VERSION 5.7 ;
  NOWIREEXTENSIONATPIN ON ;
  DIVIDERCHAR "/" ;
  BUSBITCHARS "[]" ;
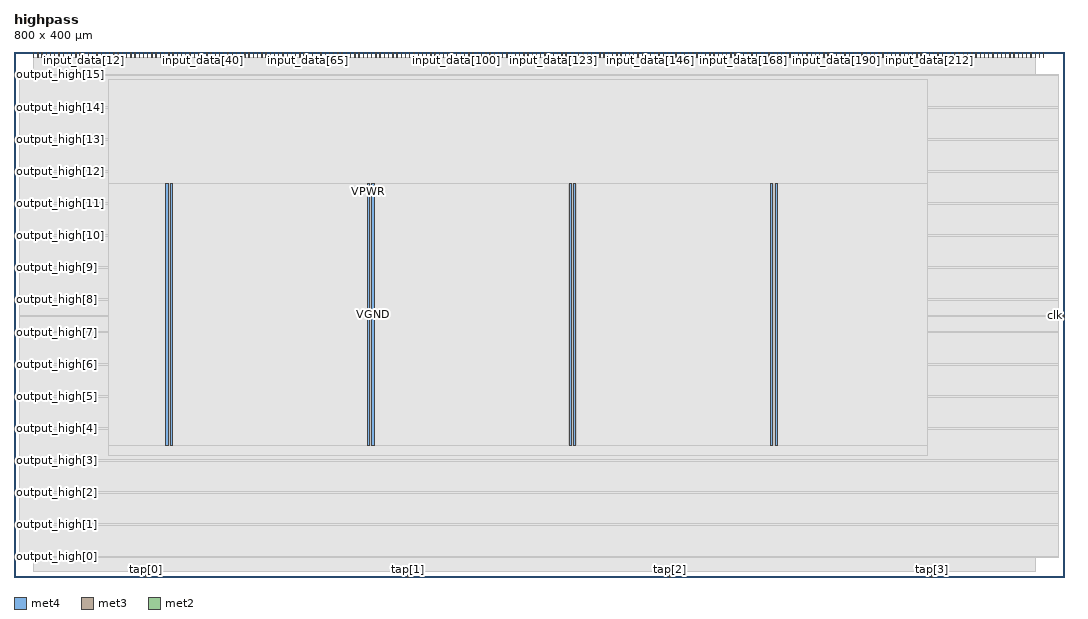
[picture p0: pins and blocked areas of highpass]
MACRO highpass
  CLASS BLOCK ;
  FOREIGN highpass ;
  ORIGIN 0.000 0.000 ;
  SIZE 800.000 BY 400.000 ;
  PIN VGND
    DIRECTION INOUT ;
    USE GROUND ;
    PORT
      LAYER met4 ;
        RECT 119.100 100.400 120.700 299.440 ;
    END
    PORT
      LAYER met4 ;
        RECT 272.700 100.400 274.300 299.440 ;
    END
    PORT
      LAYER met4 ;
        RECT 426.300 100.400 427.900 299.440 ;
    END
    PORT
      LAYER met4 ;
        RECT 579.900 100.400 581.500 299.440 ;
    END
  END VGND
  PIN VPWR
    DIRECTION INOUT ;
    USE POWER ;
    PORT
      LAYER met4 ;
        RECT 115.800 100.400 117.400 299.440 ;
    END
    PORT
      LAYER met4 ;
        RECT 269.400 100.400 271.000 299.440 ;
    END
    PORT
      LAYER met4 ;
        RECT 423.000 100.400 424.600 299.440 ;
    END
    PORT
      LAYER met4 ;
        RECT 576.600 100.400 578.200 299.440 ;
    END
  END VPWR
  PIN clk
    DIRECTION INPUT ;
    USE SIGNAL ;
    ANTENNAGATEAREA 0.852000 ;
    ANTENNADIFFAREA 0.434700 ;
    PORT
      LAYER met3 ;
        RECT 796.000 198.600 800.000 199.200 ;
    END
  END clk
  PIN input_data[0]
    DIRECTION INPUT ;
    USE SIGNAL ;
    ANTENNAGATEAREA 0.213000 ;
    ANTENNADIFFAREA 0.869400 ;
    PORT
      LAYER met2 ;
        RECT 14.810 396.000 15.090 400.000 ;
    END
  END input_data[0]
  PIN input_data[100]
    DIRECTION INPUT ;
    USE SIGNAL ;
    ANTENNAGATEAREA 0.196500 ;
    ANTENNADIFFAREA 0.434700 ;
    PORT
      LAYER met2 ;
        RECT 336.810 396.000 337.090 400.000 ;
    END
  END input_data[100]
  PIN input_data[101]
    DIRECTION INPUT ;
    USE SIGNAL ;
    ANTENNAGATEAREA 0.196500 ;
    ANTENNADIFFAREA 0.434700 ;
    PORT
      LAYER met2 ;
        RECT 340.030 396.000 340.310 400.000 ;
    END
  END input_data[101]
  PIN input_data[102]
    DIRECTION INPUT ;
    USE SIGNAL ;
    ANTENNAGATEAREA 0.213000 ;
    ANTENNADIFFAREA 0.434700 ;
    PORT
      LAYER met2 ;
        RECT 343.250 396.000 343.530 400.000 ;
    END
  END input_data[102]
  PIN input_data[103]
    DIRECTION INPUT ;
    USE SIGNAL ;
    ANTENNAGATEAREA 0.196500 ;
    ANTENNADIFFAREA 0.434700 ;
    PORT
      LAYER met2 ;
        RECT 346.470 396.000 346.750 400.000 ;
    END
  END input_data[103]
  PIN input_data[104]
    DIRECTION INPUT ;
    USE SIGNAL ;
    ANTENNAGATEAREA 0.196500 ;
    ANTENNADIFFAREA 0.434700 ;
    PORT
      LAYER met2 ;
        RECT 349.690 396.000 349.970 400.000 ;
    END
  END input_data[104]
  PIN input_data[105]
    DIRECTION INPUT ;
    USE SIGNAL ;
    ANTENNAGATEAREA 0.196500 ;
    ANTENNADIFFAREA 0.434700 ;
    PORT
      LAYER met2 ;
        RECT 352.910 396.000 353.190 400.000 ;
    END
  END input_data[105]
  PIN input_data[106]
    DIRECTION INPUT ;
    USE SIGNAL ;
    ANTENNAGATEAREA 0.196500 ;
    ANTENNADIFFAREA 0.434700 ;
    PORT
      LAYER met2 ;
        RECT 356.130 396.000 356.410 400.000 ;
    END
  END input_data[106]
  PIN input_data[107]
    DIRECTION INPUT ;
    USE SIGNAL ;
    ANTENNAGATEAREA 0.196500 ;
    ANTENNADIFFAREA 0.434700 ;
    PORT
      LAYER met2 ;
        RECT 359.350 396.000 359.630 400.000 ;
    END
  END input_data[107]
  PIN input_data[108]
    DIRECTION INPUT ;
    USE SIGNAL ;
    ANTENNAGATEAREA 0.159000 ;
    ANTENNADIFFAREA 0.434700 ;
    PORT
      LAYER met2 ;
        RECT 362.570 396.000 362.850 400.000 ;
    END
  END input_data[108]
  PIN input_data[109]
    DIRECTION INPUT ;
    USE SIGNAL ;
    ANTENNAGATEAREA 0.196500 ;
    ANTENNADIFFAREA 0.434700 ;
    PORT
      LAYER met2 ;
        RECT 365.790 396.000 366.070 400.000 ;
    END
  END input_data[109]
  PIN input_data[10]
    DIRECTION INPUT ;
    USE SIGNAL ;
    ANTENNAGATEAREA 0.247500 ;
    ANTENNADIFFAREA 0.869400 ;
    PORT
      LAYER met2 ;
        RECT 47.010 396.000 47.290 400.000 ;
    END
  END input_data[10]
  PIN input_data[110]
    DIRECTION INPUT ;
    USE SIGNAL ;
    ANTENNAGATEAREA 0.196500 ;
    ANTENNADIFFAREA 0.434700 ;
    PORT
      LAYER met2 ;
        RECT 369.010 396.000 369.290 400.000 ;
    END
  END input_data[110]
  PIN input_data[111]
    DIRECTION INPUT ;
    USE SIGNAL ;
    ANTENNAGATEAREA 0.196500 ;
    ANTENNADIFFAREA 0.434700 ;
    PORT
      LAYER met2 ;
        RECT 372.230 396.000 372.510 400.000 ;
    END
  END input_data[111]
  PIN input_data[112]
    DIRECTION INPUT ;
    USE SIGNAL ;
    ANTENNAGATEAREA 0.213000 ;
    ANTENNADIFFAREA 0.434700 ;
    PORT
      LAYER met2 ;
        RECT 375.450 396.000 375.730 400.000 ;
    END
  END input_data[112]
  PIN input_data[113]
    DIRECTION INPUT ;
    USE SIGNAL ;
    ANTENNAGATEAREA 0.126000 ;
    ANTENNADIFFAREA 0.869400 ;
    PORT
      LAYER met2 ;
        RECT 378.670 396.000 378.950 400.000 ;
    END
  END input_data[113]
  PIN input_data[114]
    DIRECTION INPUT ;
    USE SIGNAL ;
    ANTENNAGATEAREA 0.213000 ;
    ANTENNADIFFAREA 0.434700 ;
    PORT
      LAYER met2 ;
        RECT 381.890 396.000 382.170 400.000 ;
    END
  END input_data[114]
  PIN input_data[115]
    DIRECTION INPUT ;
    USE SIGNAL ;
    ANTENNAGATEAREA 0.213000 ;
    ANTENNADIFFAREA 0.434700 ;
    PORT
      LAYER met2 ;
        RECT 385.110 396.000 385.390 400.000 ;
    END
  END input_data[115]
  PIN input_data[116]
    DIRECTION INPUT ;
    USE SIGNAL ;
    ANTENNAGATEAREA 0.213000 ;
    ANTENNADIFFAREA 0.434700 ;
    PORT
      LAYER met2 ;
        RECT 388.330 396.000 388.610 400.000 ;
    END
  END input_data[116]
  PIN input_data[117]
    DIRECTION INPUT ;
    USE SIGNAL ;
    ANTENNAGATEAREA 0.196500 ;
    ANTENNADIFFAREA 0.869400 ;
    PORT
      LAYER met2 ;
        RECT 391.550 396.000 391.830 400.000 ;
    END
  END input_data[117]
  PIN input_data[118]
    DIRECTION INPUT ;
    USE SIGNAL ;
    ANTENNAGATEAREA 0.126000 ;
    ANTENNADIFFAREA 0.434700 ;
    PORT
      LAYER met2 ;
        RECT 394.770 396.000 395.050 400.000 ;
    END
  END input_data[118]
  PIN input_data[119]
    DIRECTION INPUT ;
    USE SIGNAL ;
    ANTENNAGATEAREA 0.213000 ;
    ANTENNADIFFAREA 0.434700 ;
    PORT
      LAYER met2 ;
        RECT 397.990 396.000 398.270 400.000 ;
    END
  END input_data[119]
  PIN input_data[11]
    DIRECTION INPUT ;
    USE SIGNAL ;
    ANTENNAGATEAREA 0.213000 ;
    ANTENNADIFFAREA 0.869400 ;
    PORT
      LAYER met2 ;
        RECT 50.230 396.000 50.510 400.000 ;
    END
  END input_data[11]
  PIN input_data[120]
    DIRECTION INPUT ;
    USE SIGNAL ;
    ANTENNAGATEAREA 0.213000 ;
    ANTENNADIFFAREA 0.869400 ;
    PORT
      LAYER met2 ;
        RECT 401.210 396.000 401.490 400.000 ;
    END
  END input_data[120]
  PIN input_data[121]
    DIRECTION INPUT ;
    USE SIGNAL ;
    ANTENNAGATEAREA 0.213000 ;
    ANTENNADIFFAREA 0.434700 ;
    PORT
      LAYER met2 ;
        RECT 404.430 396.000 404.710 400.000 ;
    END
  END input_data[121]
  PIN input_data[122]
    DIRECTION INPUT ;
    USE SIGNAL ;
    ANTENNAGATEAREA 0.213000 ;
    ANTENNADIFFAREA 0.869400 ;
    PORT
      LAYER met2 ;
        RECT 407.650 396.000 407.930 400.000 ;
    END
  END input_data[122]
  PIN input_data[123]
    DIRECTION INPUT ;
    USE SIGNAL ;
    ANTENNAGATEAREA 0.213000 ;
    ANTENNADIFFAREA 0.434700 ;
    PORT
      LAYER met2 ;
        RECT 410.870 396.000 411.150 400.000 ;
    END
  END input_data[123]
  PIN input_data[124]
    DIRECTION INPUT ;
    USE SIGNAL ;
    ANTENNAGATEAREA 0.159000 ;
    ANTENNADIFFAREA 0.869400 ;
    PORT
      LAYER met2 ;
        RECT 414.090 396.000 414.370 400.000 ;
    END
  END input_data[124]
  PIN input_data[125]
    DIRECTION INPUT ;
    USE SIGNAL ;
    ANTENNAGATEAREA 0.196500 ;
    ANTENNADIFFAREA 0.869400 ;
    PORT
      LAYER met2 ;
        RECT 417.310 396.000 417.590 400.000 ;
    END
  END input_data[125]
  PIN input_data[126]
    DIRECTION INPUT ;
    USE SIGNAL ;
    ANTENNAGATEAREA 0.126000 ;
    ANTENNADIFFAREA 0.434700 ;
    PORT
      LAYER met2 ;
        RECT 420.530 396.000 420.810 400.000 ;
    END
  END input_data[126]
  PIN input_data[127]
    DIRECTION INPUT ;
    USE SIGNAL ;
    PORT
      LAYER met2 ;
        RECT 423.750 396.000 424.030 400.000 ;
    END
  END input_data[127]
  PIN input_data[128]
    DIRECTION INPUT ;
    USE SIGNAL ;
    ANTENNAGATEAREA 0.159000 ;
    ANTENNADIFFAREA 0.434700 ;
    PORT
      LAYER met2 ;
        RECT 426.970 396.000 427.250 400.000 ;
    END
  END input_data[128]
  PIN input_data[129]
    DIRECTION INPUT ;
    USE SIGNAL ;
    ANTENNAGATEAREA 0.196500 ;
    ANTENNADIFFAREA 0.434700 ;
    PORT
      LAYER met2 ;
        RECT 430.190 396.000 430.470 400.000 ;
    END
  END input_data[129]
  PIN input_data[12]
    DIRECTION INPUT ;
    USE SIGNAL ;
    ANTENNAGATEAREA 0.426000 ;
    ANTENNADIFFAREA 0.434700 ;
    PORT
      LAYER met2 ;
        RECT 53.450 396.000 53.730 400.000 ;
    END
  END input_data[12]
  PIN input_data[130]
    DIRECTION INPUT ;
    USE SIGNAL ;
    ANTENNAGATEAREA 0.213000 ;
    ANTENNADIFFAREA 0.434700 ;
    PORT
      LAYER met2 ;
        RECT 433.410 396.000 433.690 400.000 ;
    END
  END input_data[130]
  PIN input_data[131]
    DIRECTION INPUT ;
    USE SIGNAL ;
    ANTENNAGATEAREA 0.213000 ;
    ANTENNADIFFAREA 0.434700 ;
    PORT
      LAYER met2 ;
        RECT 436.630 396.000 436.910 400.000 ;
    END
  END input_data[131]
  PIN input_data[132]
    DIRECTION INPUT ;
    USE SIGNAL ;
    ANTENNAGATEAREA 0.213000 ;
    ANTENNADIFFAREA 0.434700 ;
    PORT
      LAYER met2 ;
        RECT 439.850 396.000 440.130 400.000 ;
    END
  END input_data[132]
  PIN input_data[133]
    DIRECTION INPUT ;
    USE SIGNAL ;
    ANTENNAGATEAREA 0.247500 ;
    ANTENNADIFFAREA 0.434700 ;
    PORT
      LAYER met2 ;
        RECT 443.070 396.000 443.350 400.000 ;
    END
  END input_data[133]
  PIN input_data[134]
    DIRECTION INPUT ;
    USE SIGNAL ;
    ANTENNAGATEAREA 0.213000 ;
    ANTENNADIFFAREA 0.434700 ;
    PORT
      LAYER met2 ;
        RECT 446.290 396.000 446.570 400.000 ;
    END
  END input_data[134]
  PIN input_data[135]
    DIRECTION INPUT ;
    USE SIGNAL ;
    ANTENNAGATEAREA 0.213000 ;
    ANTENNADIFFAREA 0.434700 ;
    PORT
      LAYER met2 ;
        RECT 449.510 396.000 449.790 400.000 ;
    END
  END input_data[135]
  PIN input_data[136]
    DIRECTION INPUT ;
    USE SIGNAL ;
    ANTENNAGATEAREA 0.426000 ;
    ANTENNADIFFAREA 0.434700 ;
    PORT
      LAYER met2 ;
        RECT 452.730 396.000 453.010 400.000 ;
    END
  END input_data[136]
  PIN input_data[137]
    DIRECTION INPUT ;
    USE SIGNAL ;
    ANTENNAGATEAREA 0.247500 ;
    ANTENNADIFFAREA 0.434700 ;
    PORT
      LAYER met2 ;
        RECT 455.950 396.000 456.230 400.000 ;
    END
  END input_data[137]
  PIN input_data[138]
    DIRECTION INPUT ;
    USE SIGNAL ;
    ANTENNAGATEAREA 0.159000 ;
    ANTENNADIFFAREA 0.434700 ;
    PORT
      LAYER met2 ;
        RECT 459.170 396.000 459.450 400.000 ;
    END
  END input_data[138]
  PIN input_data[139]
    DIRECTION INPUT ;
    USE SIGNAL ;
    ANTENNAGATEAREA 0.247500 ;
    ANTENNADIFFAREA 0.434700 ;
    PORT
      LAYER met2 ;
        RECT 462.390 396.000 462.670 400.000 ;
    END
  END input_data[139]
  PIN input_data[13]
    DIRECTION INPUT ;
    USE SIGNAL ;
    ANTENNAGATEAREA 0.247500 ;
    ANTENNADIFFAREA 0.869400 ;
    PORT
      LAYER met2 ;
        RECT 56.670 396.000 56.950 400.000 ;
    END
  END input_data[13]
  PIN input_data[140]
    DIRECTION INPUT ;
    USE SIGNAL ;
    ANTENNAGATEAREA 0.247500 ;
    ANTENNADIFFAREA 0.434700 ;
    PORT
      LAYER met2 ;
        RECT 465.610 396.000 465.890 400.000 ;
    END
  END input_data[140]
  PIN input_data[141]
    DIRECTION INPUT ;
    USE SIGNAL ;
    ANTENNAGATEAREA 0.213000 ;
    ANTENNADIFFAREA 0.434700 ;
    PORT
      LAYER met2 ;
        RECT 468.830 396.000 469.110 400.000 ;
    END
  END input_data[141]
  PIN input_data[142]
    DIRECTION INPUT ;
    USE SIGNAL ;
    ANTENNAGATEAREA 0.196500 ;
    ANTENNADIFFAREA 0.434700 ;
    PORT
      LAYER met2 ;
        RECT 472.050 396.000 472.330 400.000 ;
    END
  END input_data[142]
  PIN input_data[143]
    DIRECTION INPUT ;
    USE SIGNAL ;
    ANTENNAGATEAREA 0.126000 ;
    ANTENNADIFFAREA 0.434700 ;
    PORT
      LAYER met2 ;
        RECT 475.270 396.000 475.550 400.000 ;
    END
  END input_data[143]
  PIN input_data[144]
    DIRECTION INPUT ;
    USE SIGNAL ;
    ANTENNAGATEAREA 0.126000 ;
    ANTENNADIFFAREA 0.434700 ;
    PORT
      LAYER met2 ;
        RECT 478.490 396.000 478.770 400.000 ;
    END
  END input_data[144]
  PIN input_data[145]
    DIRECTION INPUT ;
    USE SIGNAL ;
    ANTENNAGATEAREA 0.213000 ;
    ANTENNADIFFAREA 0.434700 ;
    PORT
      LAYER met2 ;
        RECT 481.710 396.000 481.990 400.000 ;
    END
  END input_data[145]
  PIN input_data[146]
    DIRECTION INPUT ;
    USE SIGNAL ;
    ANTENNAGATEAREA 0.196500 ;
    ANTENNADIFFAREA 0.434700 ;
    PORT
      LAYER met2 ;
        RECT 484.930 396.000 485.210 400.000 ;
    END
  END input_data[146]
  PIN input_data[147]
    DIRECTION INPUT ;
    USE SIGNAL ;
    ANTENNAGATEAREA 0.126000 ;
    ANTENNADIFFAREA 0.434700 ;
    PORT
      LAYER met2 ;
        RECT 488.150 396.000 488.430 400.000 ;
    END
  END input_data[147]
  PIN input_data[148]
    DIRECTION INPUT ;
    USE SIGNAL ;
    ANTENNAGATEAREA 0.213000 ;
    ANTENNADIFFAREA 0.434700 ;
    PORT
      LAYER met2 ;
        RECT 491.370 396.000 491.650 400.000 ;
    END
  END input_data[148]
  PIN input_data[149]
    DIRECTION INPUT ;
    USE SIGNAL ;
    ANTENNAGATEAREA 0.159000 ;
    ANTENNADIFFAREA 0.434700 ;
    PORT
      LAYER met2 ;
        RECT 494.590 396.000 494.870 400.000 ;
    END
  END input_data[149]
  PIN input_data[14]
    DIRECTION INPUT ;
    USE SIGNAL ;
    ANTENNAGATEAREA 0.159000 ;
    ANTENNADIFFAREA 0.869400 ;
    PORT
      LAYER met2 ;
        RECT 59.890 396.000 60.170 400.000 ;
    END
  END input_data[14]
  PIN input_data[150]
    DIRECTION INPUT ;
    USE SIGNAL ;
    ANTENNAGATEAREA 0.213000 ;
    ANTENNADIFFAREA 0.434700 ;
    PORT
      LAYER met2 ;
        RECT 497.810 396.000 498.090 400.000 ;
    END
  END input_data[150]
  PIN input_data[151]
    DIRECTION INPUT ;
    USE SIGNAL ;
    ANTENNAGATEAREA 0.159000 ;
    ANTENNADIFFAREA 0.434700 ;
    PORT
      LAYER met2 ;
        RECT 501.030 396.000 501.310 400.000 ;
    END
  END input_data[151]
  PIN input_data[152]
    DIRECTION INPUT ;
    USE SIGNAL ;
    ANTENNAGATEAREA 0.159000 ;
    ANTENNADIFFAREA 0.434700 ;
    PORT
      LAYER met2 ;
        RECT 504.250 396.000 504.530 400.000 ;
    END
  END input_data[152]
  PIN input_data[153]
    DIRECTION INPUT ;
    USE SIGNAL ;
    ANTENNAGATEAREA 0.126000 ;
    ANTENNADIFFAREA 0.434700 ;
    PORT
      LAYER met2 ;
        RECT 507.470 396.000 507.750 400.000 ;
    END
  END input_data[153]
  PIN input_data[154]
    DIRECTION INPUT ;
    USE SIGNAL ;
    ANTENNAGATEAREA 0.126000 ;
    ANTENNADIFFAREA 0.434700 ;
    PORT
      LAYER met2 ;
        RECT 510.690 396.000 510.970 400.000 ;
    END
  END input_data[154]
  PIN input_data[155]
    DIRECTION INPUT ;
    USE SIGNAL ;
    ANTENNAGATEAREA 0.196500 ;
    ANTENNADIFFAREA 0.434700 ;
    PORT
      LAYER met2 ;
        RECT 513.910 396.000 514.190 400.000 ;
    END
  END input_data[155]
  PIN input_data[156]
    DIRECTION INPUT ;
    USE SIGNAL ;
    ANTENNAGATEAREA 0.159000 ;
    ANTENNADIFFAREA 0.434700 ;
    PORT
      LAYER met2 ;
        RECT 517.130 396.000 517.410 400.000 ;
    END
  END input_data[156]
  PIN input_data[157]
    DIRECTION INPUT ;
    USE SIGNAL ;
    ANTENNAGATEAREA 0.213000 ;
    ANTENNADIFFAREA 0.434700 ;
    PORT
      LAYER met2 ;
        RECT 520.350 396.000 520.630 400.000 ;
    END
  END input_data[157]
  PIN input_data[158]
    DIRECTION INPUT ;
    USE SIGNAL ;
    ANTENNAGATEAREA 0.196500 ;
    ANTENNADIFFAREA 0.434700 ;
    PORT
      LAYER met2 ;
        RECT 523.570 396.000 523.850 400.000 ;
    END
  END input_data[158]
  PIN input_data[159]
    DIRECTION INPUT ;
    USE SIGNAL ;
    ANTENNAGATEAREA 0.196500 ;
    ANTENNADIFFAREA 0.434700 ;
    PORT
      LAYER met2 ;
        RECT 526.790 396.000 527.070 400.000 ;
    END
  END input_data[159]
  PIN input_data[15]
    DIRECTION INPUT ;
    USE SIGNAL ;
    ANTENNAGATEAREA 0.126000 ;
    ANTENNADIFFAREA 0.869400 ;
    PORT
      LAYER met2 ;
        RECT 63.110 396.000 63.390 400.000 ;
    END
  END input_data[15]
  PIN input_data[160]
    DIRECTION INPUT ;
    USE SIGNAL ;
    ANTENNAGATEAREA 0.247500 ;
    ANTENNADIFFAREA 0.434700 ;
    PORT
      LAYER met2 ;
        RECT 530.010 396.000 530.290 400.000 ;
    END
  END input_data[160]
  PIN input_data[161]
    DIRECTION INPUT ;
    USE SIGNAL ;
    ANTENNAGATEAREA 0.247500 ;
    ANTENNADIFFAREA 0.434700 ;
    PORT
      LAYER met2 ;
        RECT 533.230 396.000 533.510 400.000 ;
    END
  END input_data[161]
  PIN input_data[162]
    DIRECTION INPUT ;
    USE SIGNAL ;
    ANTENNAGATEAREA 0.247500 ;
    ANTENNADIFFAREA 0.434700 ;
    PORT
      LAYER met2 ;
        RECT 536.450 396.000 536.730 400.000 ;
    END
  END input_data[162]
  PIN input_data[163]
    DIRECTION INPUT ;
    USE SIGNAL ;
    ANTENNAGATEAREA 0.213000 ;
    ANTENNADIFFAREA 0.434700 ;
    PORT
      LAYER met2 ;
        RECT 539.670 396.000 539.950 400.000 ;
    END
  END input_data[163]
  PIN input_data[164]
    DIRECTION INPUT ;
    USE SIGNAL ;
    ANTENNAGATEAREA 0.126000 ;
    ANTENNADIFFAREA 0.434700 ;
    PORT
      LAYER met2 ;
        RECT 542.890 396.000 543.170 400.000 ;
    END
  END input_data[164]
  PIN input_data[165]
    DIRECTION INPUT ;
    USE SIGNAL ;
    ANTENNAGATEAREA 0.213000 ;
    ANTENNADIFFAREA 0.434700 ;
    PORT
      LAYER met2 ;
        RECT 546.110 396.000 546.390 400.000 ;
    END
  END input_data[165]
  PIN input_data[166]
    DIRECTION INPUT ;
    USE SIGNAL ;
    ANTENNAGATEAREA 0.213000 ;
    ANTENNADIFFAREA 0.434700 ;
    PORT
      LAYER met2 ;
        RECT 549.330 396.000 549.610 400.000 ;
    END
  END input_data[166]
  PIN input_data[167]
    DIRECTION INPUT ;
    USE SIGNAL ;
    ANTENNAGATEAREA 0.196500 ;
    ANTENNADIFFAREA 0.869400 ;
    PORT
      LAYER met2 ;
        RECT 552.550 396.000 552.830 400.000 ;
    END
  END input_data[167]
  PIN input_data[168]
    DIRECTION INPUT ;
    USE SIGNAL ;
    ANTENNAGATEAREA 0.196500 ;
    ANTENNADIFFAREA 0.434700 ;
    PORT
      LAYER met2 ;
        RECT 555.770 396.000 556.050 400.000 ;
    END
  END input_data[168]
  PIN input_data[169]
    DIRECTION INPUT ;
    USE SIGNAL ;
    ANTENNAGATEAREA 0.196500 ;
    ANTENNADIFFAREA 0.434700 ;
    PORT
      LAYER met2 ;
        RECT 558.990 396.000 559.270 400.000 ;
    END
  END input_data[169]
  PIN input_data[16]
    DIRECTION INPUT ;
    USE SIGNAL ;
    ANTENNAGATEAREA 0.247500 ;
    ANTENNADIFFAREA 0.434700 ;
    PORT
      LAYER met2 ;
        RECT 66.330 396.000 66.610 400.000 ;
    END
  END input_data[16]
  PIN input_data[170]
    DIRECTION INPUT ;
    USE SIGNAL ;
    ANTENNAGATEAREA 0.196500 ;
    ANTENNADIFFAREA 0.434700 ;
    PORT
      LAYER met2 ;
        RECT 562.210 396.000 562.490 400.000 ;
    END
  END input_data[170]
  PIN input_data[171]
    DIRECTION INPUT ;
    USE SIGNAL ;
    ANTENNAGATEAREA 0.213000 ;
    ANTENNADIFFAREA 0.869400 ;
    PORT
      LAYER met2 ;
        RECT 565.430 396.000 565.710 400.000 ;
    END
  END input_data[171]
  PIN input_data[172]
    DIRECTION INPUT ;
    USE SIGNAL ;
    ANTENNAGATEAREA 0.213000 ;
    ANTENNADIFFAREA 0.434700 ;
    PORT
      LAYER met2 ;
        RECT 568.650 396.000 568.930 400.000 ;
    END
  END input_data[172]
  PIN input_data[173]
    DIRECTION INPUT ;
    USE SIGNAL ;
    ANTENNAGATEAREA 0.247500 ;
    ANTENNADIFFAREA 0.434700 ;
    PORT
      LAYER met2 ;
        RECT 571.870 396.000 572.150 400.000 ;
    END
  END input_data[173]
  PIN input_data[174]
    DIRECTION INPUT ;
    USE SIGNAL ;
    ANTENNAGATEAREA 0.196500 ;
    ANTENNADIFFAREA 0.434700 ;
    PORT
      LAYER met2 ;
        RECT 575.090 396.000 575.370 400.000 ;
    END
  END input_data[174]
  PIN input_data[175]
    DIRECTION INPUT ;
    USE SIGNAL ;
    ANTENNAGATEAREA 0.196500 ;
    ANTENNADIFFAREA 0.869400 ;
    PORT
      LAYER met2 ;
        RECT 578.310 396.000 578.590 400.000 ;
    END
  END input_data[175]
  PIN input_data[176]
    DIRECTION INPUT ;
    USE SIGNAL ;
    ANTENNAGATEAREA 0.196500 ;
    ANTENNADIFFAREA 0.869400 ;
    PORT
      LAYER met2 ;
        RECT 581.530 396.000 581.810 400.000 ;
    END
  END input_data[176]
  PIN input_data[177]
    DIRECTION INPUT ;
    USE SIGNAL ;
    ANTENNAGATEAREA 0.213000 ;
    ANTENNADIFFAREA 0.434700 ;
    PORT
      LAYER met2 ;
        RECT 584.750 396.000 585.030 400.000 ;
    END
  END input_data[177]
  PIN input_data[178]
    DIRECTION INPUT ;
    USE SIGNAL ;
    ANTENNAGATEAREA 0.247500 ;
    ANTENNADIFFAREA 0.434700 ;
    PORT
      LAYER met2 ;
        RECT 587.970 396.000 588.250 400.000 ;
    END
  END input_data[178]
  PIN input_data[179]
    DIRECTION INPUT ;
    USE SIGNAL ;
    ANTENNAGATEAREA 0.247500 ;
    ANTENNADIFFAREA 0.434700 ;
    PORT
      LAYER met2 ;
        RECT 591.190 396.000 591.470 400.000 ;
    END
  END input_data[179]
  PIN input_data[17]
    DIRECTION INPUT ;
    USE SIGNAL ;
    ANTENNAGATEAREA 0.213000 ;
    ANTENNADIFFAREA 0.434700 ;
    PORT
      LAYER met2 ;
        RECT 69.550 396.000 69.830 400.000 ;
    END
  END input_data[17]
  PIN input_data[180]
    DIRECTION INPUT ;
    USE SIGNAL ;
    ANTENNAGATEAREA 0.247500 ;
    ANTENNADIFFAREA 0.434700 ;
    PORT
      LAYER met2 ;
        RECT 594.410 396.000 594.690 400.000 ;
    END
  END input_data[180]
  PIN input_data[181]
    DIRECTION INPUT ;
    USE SIGNAL ;
    ANTENNAGATEAREA 0.213000 ;
    ANTENNADIFFAREA 0.434700 ;
    PORT
      LAYER met2 ;
        RECT 597.630 396.000 597.910 400.000 ;
    END
  END input_data[181]
  PIN input_data[182]
    DIRECTION INPUT ;
    USE SIGNAL ;
    ANTENNAGATEAREA 0.159000 ;
    ANTENNADIFFAREA 0.434700 ;
    PORT
      LAYER met2 ;
        RECT 600.850 396.000 601.130 400.000 ;
    END
  END input_data[182]
  PIN input_data[183]
    DIRECTION INPUT ;
    USE SIGNAL ;
    ANTENNAGATEAREA 0.159000 ;
    ANTENNADIFFAREA 0.869400 ;
    PORT
      LAYER met2 ;
        RECT 604.070 396.000 604.350 400.000 ;
    END
  END input_data[183]
  PIN input_data[184]
    DIRECTION INPUT ;
    USE SIGNAL ;
    ANTENNAGATEAREA 0.159000 ;
    ANTENNADIFFAREA 0.434700 ;
    PORT
      LAYER met2 ;
        RECT 607.290 396.000 607.570 400.000 ;
    END
  END input_data[184]
  PIN input_data[185]
    DIRECTION INPUT ;
    USE SIGNAL ;
    ANTENNAGATEAREA 0.213000 ;
    ANTENNADIFFAREA 0.434700 ;
    PORT
      LAYER met2 ;
        RECT 610.510 396.000 610.790 400.000 ;
    END
  END input_data[185]
  PIN input_data[186]
    DIRECTION INPUT ;
    USE SIGNAL ;
    ANTENNAGATEAREA 0.213000 ;
    ANTENNADIFFAREA 0.434700 ;
    PORT
      LAYER met2 ;
        RECT 613.730 396.000 614.010 400.000 ;
    END
  END input_data[186]
  PIN input_data[187]
    DIRECTION INPUT ;
    USE SIGNAL ;
    ANTENNAGATEAREA 0.213000 ;
    ANTENNADIFFAREA 0.434700 ;
    PORT
      LAYER met2 ;
        RECT 616.950 396.000 617.230 400.000 ;
    END
  END input_data[187]
  PIN input_data[188]
    DIRECTION INPUT ;
    USE SIGNAL ;
    ANTENNAGATEAREA 0.213000 ;
    ANTENNADIFFAREA 0.434700 ;
    PORT
      LAYER met2 ;
        RECT 620.170 396.000 620.450 400.000 ;
    END
  END input_data[188]
  PIN input_data[189]
    DIRECTION INPUT ;
    USE SIGNAL ;
    ANTENNAGATEAREA 0.196500 ;
    ANTENNADIFFAREA 0.434700 ;
    PORT
      LAYER met2 ;
        RECT 623.390 396.000 623.670 400.000 ;
    END
  END input_data[189]
  PIN input_data[18]
    DIRECTION INPUT ;
    USE SIGNAL ;
    ANTENNAGATEAREA 0.159000 ;
    ANTENNADIFFAREA 0.869400 ;
    PORT
      LAYER met2 ;
        RECT 72.770 396.000 73.050 400.000 ;
    END
  END input_data[18]
  PIN input_data[190]
    DIRECTION INPUT ;
    USE SIGNAL ;
    ANTENNAGATEAREA 0.196500 ;
    ANTENNADIFFAREA 0.434700 ;
    PORT
      LAYER met2 ;
        RECT 626.610 396.000 626.890 400.000 ;
    END
  END input_data[190]
  PIN input_data[191]
    DIRECTION INPUT ;
    USE SIGNAL ;
    PORT
      LAYER met2 ;
        RECT 629.830 396.000 630.110 400.000 ;
    END
  END input_data[191]
  PIN input_data[192]
    DIRECTION INPUT ;
    USE SIGNAL ;
    ANTENNAGATEAREA 0.213000 ;
    ANTENNADIFFAREA 0.434700 ;
    PORT
      LAYER met2 ;
        RECT 633.050 396.000 633.330 400.000 ;
    END
  END input_data[192]
  PIN input_data[193]
    DIRECTION INPUT ;
    USE SIGNAL ;
    ANTENNAGATEAREA 0.126000 ;
    ANTENNADIFFAREA 0.434700 ;
    PORT
      LAYER met2 ;
        RECT 636.270 396.000 636.550 400.000 ;
    END
  END input_data[193]
  PIN input_data[194]
    DIRECTION INPUT ;
    USE SIGNAL ;
    ANTENNAGATEAREA 0.213000 ;
    ANTENNADIFFAREA 0.434700 ;
    PORT
      LAYER met2 ;
        RECT 639.490 396.000 639.770 400.000 ;
    END
  END input_data[194]
  PIN input_data[195]
    DIRECTION INPUT ;
    USE SIGNAL ;
    ANTENNAGATEAREA 0.159000 ;
    ANTENNADIFFAREA 0.434700 ;
    PORT
      LAYER met2 ;
        RECT 642.710 396.000 642.990 400.000 ;
    END
  END input_data[195]
  PIN input_data[196]
    DIRECTION INPUT ;
    USE SIGNAL ;
    ANTENNAGATEAREA 0.126000 ;
    ANTENNADIFFAREA 0.434700 ;
    PORT
      LAYER met2 ;
        RECT 645.930 396.000 646.210 400.000 ;
    END
  END input_data[196]
  PIN input_data[197]
    DIRECTION INPUT ;
    USE SIGNAL ;
    ANTENNAGATEAREA 0.126000 ;
    ANTENNADIFFAREA 0.434700 ;
    PORT
      LAYER met2 ;
        RECT 649.150 396.000 649.430 400.000 ;
    END
  END input_data[197]
  PIN input_data[198]
    DIRECTION INPUT ;
    USE SIGNAL ;
    ANTENNAGATEAREA 0.126000 ;
    ANTENNADIFFAREA 0.434700 ;
    PORT
      LAYER met2 ;
        RECT 652.370 396.000 652.650 400.000 ;
    END
  END input_data[198]
  PIN input_data[199]
    DIRECTION INPUT ;
    USE SIGNAL ;
    ANTENNAGATEAREA 0.126000 ;
    ANTENNADIFFAREA 0.434700 ;
    PORT
      LAYER met2 ;
        RECT 655.590 396.000 655.870 400.000 ;
    END
  END input_data[199]
  PIN input_data[19]
    DIRECTION INPUT ;
    USE SIGNAL ;
    ANTENNAGATEAREA 0.213000 ;
    ANTENNADIFFAREA 0.869400 ;
    PORT
      LAYER met2 ;
        RECT 75.990 396.000 76.270 400.000 ;
    END
  END input_data[19]
  PIN input_data[1]
    DIRECTION INPUT ;
    USE SIGNAL ;
    ANTENNAGATEAREA 0.196500 ;
    ANTENNADIFFAREA 0.869400 ;
    PORT
      LAYER met2 ;
        RECT 18.030 396.000 18.310 400.000 ;
    END
  END input_data[1]
  PIN input_data[200]
    DIRECTION INPUT ;
    USE SIGNAL ;
    ANTENNAGATEAREA 0.126000 ;
    ANTENNADIFFAREA 0.434700 ;
    PORT
      LAYER met2 ;
        RECT 658.810 396.000 659.090 400.000 ;
    END
  END input_data[200]
  PIN input_data[201]
    DIRECTION INPUT ;
    USE SIGNAL ;
    ANTENNAGATEAREA 0.126000 ;
    ANTENNADIFFAREA 0.434700 ;
    PORT
      LAYER met2 ;
        RECT 662.030 396.000 662.310 400.000 ;
    END
  END input_data[201]
  PIN input_data[202]
    DIRECTION INPUT ;
    USE SIGNAL ;
    ANTENNAGATEAREA 0.126000 ;
    ANTENNADIFFAREA 0.434700 ;
    PORT
      LAYER met2 ;
        RECT 665.250 396.000 665.530 400.000 ;
    END
  END input_data[202]
  PIN input_data[203]
    DIRECTION INPUT ;
    USE SIGNAL ;
    ANTENNAGATEAREA 0.126000 ;
    ANTENNADIFFAREA 0.434700 ;
    PORT
      LAYER met2 ;
        RECT 668.470 396.000 668.750 400.000 ;
    END
  END input_data[203]
  PIN input_data[204]
    DIRECTION INPUT ;
    USE SIGNAL ;
    ANTENNAGATEAREA 0.196500 ;
    ANTENNADIFFAREA 0.434700 ;
    PORT
      LAYER met2 ;
        RECT 671.690 396.000 671.970 400.000 ;
    END
  END input_data[204]
  PIN input_data[205]
    DIRECTION INPUT ;
    USE SIGNAL ;
    ANTENNAGATEAREA 0.196500 ;
    ANTENNADIFFAREA 0.434700 ;
    PORT
      LAYER met2 ;
        RECT 674.910 396.000 675.190 400.000 ;
    END
  END input_data[205]
  PIN input_data[206]
    DIRECTION INPUT ;
    USE SIGNAL ;
    ANTENNAGATEAREA 0.196500 ;
    ANTENNADIFFAREA 1.738800 ;
    PORT
      LAYER met2 ;
        RECT 678.130 396.000 678.410 400.000 ;
    END
  END input_data[206]
  PIN input_data[207]
    DIRECTION INPUT ;
    USE SIGNAL ;
    PORT
      LAYER met2 ;
        RECT 681.350 396.000 681.630 400.000 ;
    END
  END input_data[207]
  PIN input_data[208]
    DIRECTION INPUT ;
    USE SIGNAL ;
    PORT
      LAYER met2 ;
        RECT 684.570 396.000 684.850 400.000 ;
    END
  END input_data[208]
  PIN input_data[209]
    DIRECTION INPUT ;
    USE SIGNAL ;
    PORT
      LAYER met2 ;
        RECT 687.790 396.000 688.070 400.000 ;
    END
  END input_data[209]
  PIN input_data[20]
    DIRECTION INPUT ;
    USE SIGNAL ;
    ANTENNAGATEAREA 0.213000 ;
    ANTENNADIFFAREA 0.434700 ;
    PORT
      LAYER met2 ;
        RECT 79.210 396.000 79.490 400.000 ;
    END
  END input_data[20]
  PIN input_data[210]
    DIRECTION INPUT ;
    USE SIGNAL ;
    PORT
      LAYER met2 ;
        RECT 691.010 396.000 691.290 400.000 ;
    END
  END input_data[210]
  PIN input_data[211]
    DIRECTION INPUT ;
    USE SIGNAL ;
    PORT
      LAYER met2 ;
        RECT 694.230 396.000 694.510 400.000 ;
    END
  END input_data[211]
  PIN input_data[212]
    DIRECTION INPUT ;
    USE SIGNAL ;
    PORT
      LAYER met2 ;
        RECT 697.450 396.000 697.730 400.000 ;
    END
  END input_data[212]
  PIN input_data[213]
    DIRECTION INPUT ;
    USE SIGNAL ;
    PORT
      LAYER met2 ;
        RECT 700.670 396.000 700.950 400.000 ;
    END
  END input_data[213]
  PIN input_data[214]
    DIRECTION INPUT ;
    USE SIGNAL ;
    PORT
      LAYER met2 ;
        RECT 703.890 396.000 704.170 400.000 ;
    END
  END input_data[214]
  PIN input_data[215]
    DIRECTION INPUT ;
    USE SIGNAL ;
    PORT
      LAYER met2 ;
        RECT 707.110 396.000 707.390 400.000 ;
    END
  END input_data[215]
  PIN input_data[216]
    DIRECTION INPUT ;
    USE SIGNAL ;
    PORT
      LAYER met2 ;
        RECT 710.330 396.000 710.610 400.000 ;
    END
  END input_data[216]
  PIN input_data[217]
    DIRECTION INPUT ;
    USE SIGNAL ;
    PORT
      LAYER met2 ;
        RECT 713.550 396.000 713.830 400.000 ;
    END
  END input_data[217]
  PIN input_data[218]
    DIRECTION INPUT ;
    USE SIGNAL ;
    PORT
      LAYER met2 ;
        RECT 716.770 396.000 717.050 400.000 ;
    END
  END input_data[218]
  PIN input_data[219]
    DIRECTION INPUT ;
    USE SIGNAL ;
    PORT
      LAYER met2 ;
        RECT 719.990 396.000 720.270 400.000 ;
    END
  END input_data[219]
  PIN input_data[21]
    DIRECTION INPUT ;
    USE SIGNAL ;
    ANTENNAGATEAREA 0.159000 ;
    ANTENNADIFFAREA 0.869400 ;
    PORT
      LAYER met2 ;
        RECT 82.430 396.000 82.710 400.000 ;
    END
  END input_data[21]
  PIN input_data[220]
    DIRECTION INPUT ;
    USE SIGNAL ;
    PORT
      LAYER met2 ;
        RECT 723.210 396.000 723.490 400.000 ;
    END
  END input_data[220]
  PIN input_data[221]
    DIRECTION INPUT ;
    USE SIGNAL ;
    PORT
      LAYER met2 ;
        RECT 726.430 396.000 726.710 400.000 ;
    END
  END input_data[221]
  PIN input_data[222]
    DIRECTION INPUT ;
    USE SIGNAL ;
    PORT
      LAYER met2 ;
        RECT 729.650 396.000 729.930 400.000 ;
    END
  END input_data[222]
  PIN input_data[223]
    DIRECTION INPUT ;
    USE SIGNAL ;
    PORT
      LAYER met2 ;
        RECT 732.870 396.000 733.150 400.000 ;
    END
  END input_data[223]
  PIN input_data[224]
    DIRECTION INPUT ;
    USE SIGNAL ;
    ANTENNAGATEAREA 0.159000 ;
    ANTENNADIFFAREA 0.869400 ;
    PORT
      LAYER met2 ;
        RECT 736.090 396.000 736.370 400.000 ;
    END
  END input_data[224]
  PIN input_data[225]
    DIRECTION INPUT ;
    USE SIGNAL ;
    ANTENNAGATEAREA 0.247500 ;
    ANTENNADIFFAREA 0.434700 ;
    PORT
      LAYER met2 ;
        RECT 739.310 396.000 739.590 400.000 ;
    END
  END input_data[225]
  PIN input_data[226]
    DIRECTION INPUT ;
    USE SIGNAL ;
    ANTENNAGATEAREA 0.213000 ;
    ANTENNADIFFAREA 0.434700 ;
    PORT
      LAYER met2 ;
        RECT 742.530 396.000 742.810 400.000 ;
    END
  END input_data[226]
  PIN input_data[227]
    DIRECTION INPUT ;
    USE SIGNAL ;
    ANTENNAGATEAREA 0.213000 ;
    ANTENNADIFFAREA 0.434700 ;
    PORT
      LAYER met2 ;
        RECT 745.750 396.000 746.030 400.000 ;
    END
  END input_data[227]
  PIN input_data[228]
    DIRECTION INPUT ;
    USE SIGNAL ;
    ANTENNAGATEAREA 0.213000 ;
    ANTENNADIFFAREA 1.738800 ;
    PORT
      LAYER met2 ;
        RECT 748.970 396.000 749.250 400.000 ;
    END
  END input_data[228]
  PIN input_data[229]
    DIRECTION INPUT ;
    USE SIGNAL ;
    ANTENNAGATEAREA 0.213000 ;
    ANTENNADIFFAREA 0.869400 ;
    PORT
      LAYER met2 ;
        RECT 752.190 396.000 752.470 400.000 ;
    END
  END input_data[229]
  PIN input_data[22]
    DIRECTION INPUT ;
    USE SIGNAL ;
    ANTENNAGATEAREA 0.159000 ;
    ANTENNADIFFAREA 0.434700 ;
    PORT
      LAYER met2 ;
        RECT 85.650 396.000 85.930 400.000 ;
    END
  END input_data[22]
  PIN input_data[230]
    DIRECTION INPUT ;
    USE SIGNAL ;
    ANTENNAGATEAREA 0.213000 ;
    ANTENNADIFFAREA 0.434700 ;
    PORT
      LAYER met2 ;
        RECT 755.410 396.000 755.690 400.000 ;
    END
  END input_data[230]
  PIN input_data[231]
    DIRECTION INPUT ;
    USE SIGNAL ;
    ANTENNAGATEAREA 0.213000 ;
    ANTENNADIFFAREA 2.608200 ;
    PORT
      LAYER met2 ;
        RECT 758.630 396.000 758.910 400.000 ;
    END
  END input_data[231]
  PIN input_data[232]
    DIRECTION INPUT ;
    USE SIGNAL ;
    ANTENNAGATEAREA 0.126000 ;
    ANTENNADIFFAREA 1.304100 ;
    PORT
      LAYER met2 ;
        RECT 761.850 396.000 762.130 400.000 ;
    END
  END input_data[232]
  PIN input_data[233]
    DIRECTION INPUT ;
    USE SIGNAL ;
    ANTENNAGATEAREA 0.126000 ;
    ANTENNADIFFAREA 0.434700 ;
    PORT
      LAYER met2 ;
        RECT 765.070 396.000 765.350 400.000 ;
    END
  END input_data[233]
  PIN input_data[234]
    DIRECTION INPUT ;
    USE SIGNAL ;
    ANTENNAGATEAREA 0.126000 ;
    ANTENNADIFFAREA 1.304100 ;
    PORT
      LAYER met2 ;
        RECT 768.290 396.000 768.570 400.000 ;
    END
  END input_data[234]
  PIN input_data[235]
    DIRECTION INPUT ;
    USE SIGNAL ;
    ANTENNAGATEAREA 0.196500 ;
    ANTENNADIFFAREA 1.304100 ;
    PORT
      LAYER met2 ;
        RECT 771.510 396.000 771.790 400.000 ;
    END
  END input_data[235]
  PIN input_data[236]
    DIRECTION INPUT ;
    USE SIGNAL ;
    ANTENNAGATEAREA 0.196500 ;
    ANTENNADIFFAREA 0.434700 ;
    PORT
      LAYER met2 ;
        RECT 774.730 396.000 775.010 400.000 ;
    END
  END input_data[236]
  PIN input_data[237]
    DIRECTION INPUT ;
    USE SIGNAL ;
    ANTENNAGATEAREA 0.196500 ;
    ANTENNADIFFAREA 1.738800 ;
    PORT
      LAYER met2 ;
        RECT 777.950 396.000 778.230 400.000 ;
    END
  END input_data[237]
  PIN input_data[238]
    DIRECTION INPUT ;
    USE SIGNAL ;
    PORT
      LAYER met2 ;
        RECT 781.170 396.000 781.450 400.000 ;
    END
  END input_data[238]
  PIN input_data[239]
    DIRECTION INPUT ;
    USE SIGNAL ;
    PORT
      LAYER met2 ;
        RECT 784.390 396.000 784.670 400.000 ;
    END
  END input_data[239]
  PIN input_data[23]
    DIRECTION INPUT ;
    USE SIGNAL ;
    ANTENNAGATEAREA 0.213000 ;
    ANTENNADIFFAREA 0.869400 ;
    PORT
      LAYER met2 ;
        RECT 88.870 396.000 89.150 400.000 ;
    END
  END input_data[23]
  PIN input_data[24]
    DIRECTION INPUT ;
    USE SIGNAL ;
    ANTENNAGATEAREA 0.213000 ;
    ANTENNADIFFAREA 0.869400 ;
    PORT
      LAYER met2 ;
        RECT 92.090 396.000 92.370 400.000 ;
    END
  END input_data[24]
  PIN input_data[25]
    DIRECTION INPUT ;
    USE SIGNAL ;
    ANTENNAGATEAREA 0.159000 ;
    ANTENNADIFFAREA 0.434700 ;
    PORT
      LAYER met2 ;
        RECT 95.310 396.000 95.590 400.000 ;
    END
  END input_data[25]
  PIN input_data[26]
    DIRECTION INPUT ;
    USE SIGNAL ;
    ANTENNAGATEAREA 0.247500 ;
    ANTENNADIFFAREA 0.434700 ;
    PORT
      LAYER met2 ;
        RECT 98.530 396.000 98.810 400.000 ;
    END
  END input_data[26]
  PIN input_data[27]
    DIRECTION INPUT ;
    USE SIGNAL ;
    ANTENNAGATEAREA 0.247500 ;
    ANTENNADIFFAREA 0.434700 ;
    PORT
      LAYER met2 ;
        RECT 101.750 396.000 102.030 400.000 ;
    END
  END input_data[27]
  PIN input_data[28]
    DIRECTION INPUT ;
    USE SIGNAL ;
    ANTENNAGATEAREA 0.196500 ;
    ANTENNADIFFAREA 0.434700 ;
    PORT
      LAYER met2 ;
        RECT 104.970 396.000 105.250 400.000 ;
    END
  END input_data[28]
  PIN input_data[29]
    DIRECTION INPUT ;
    USE SIGNAL ;
    ANTENNAGATEAREA 0.213000 ;
    ANTENNADIFFAREA 0.434700 ;
    PORT
      LAYER met2 ;
        RECT 108.190 396.000 108.470 400.000 ;
    END
  END input_data[29]
  PIN input_data[2]
    DIRECTION INPUT ;
    USE SIGNAL ;
    ANTENNAGATEAREA 0.196500 ;
    ANTENNADIFFAREA 0.434700 ;
    PORT
      LAYER met2 ;
        RECT 21.250 396.000 21.530 400.000 ;
    END
  END input_data[2]
  PIN input_data[30]
    DIRECTION INPUT ;
    USE SIGNAL ;
    ANTENNAGATEAREA 0.159000 ;
    ANTENNADIFFAREA 0.869400 ;
    PORT
      LAYER met2 ;
        RECT 111.410 396.000 111.690 400.000 ;
    END
  END input_data[30]
  PIN input_data[31]
    DIRECTION INPUT ;
    USE SIGNAL ;
    ANTENNAGATEAREA 0.126000 ;
    ANTENNADIFFAREA 0.869400 ;
    PORT
      LAYER met2 ;
        RECT 114.630 396.000 114.910 400.000 ;
    END
  END input_data[31]
  PIN input_data[32]
    DIRECTION INPUT ;
    USE SIGNAL ;
    ANTENNAGATEAREA 0.196500 ;
    ANTENNADIFFAREA 0.869400 ;
    PORT
      LAYER met2 ;
        RECT 117.850 396.000 118.130 400.000 ;
    END
  END input_data[32]
  PIN input_data[33]
    DIRECTION INPUT ;
    USE SIGNAL ;
    ANTENNAGATEAREA 0.213000 ;
    ANTENNADIFFAREA 0.434700 ;
    PORT
      LAYER met2 ;
        RECT 121.070 396.000 121.350 400.000 ;
    END
  END input_data[33]
  PIN input_data[34]
    DIRECTION INPUT ;
    USE SIGNAL ;
    ANTENNAGATEAREA 0.213000 ;
    ANTENNADIFFAREA 1.304100 ;
    PORT
      LAYER met2 ;
        RECT 124.290 396.000 124.570 400.000 ;
    END
  END input_data[34]
  PIN input_data[35]
    DIRECTION INPUT ;
    USE SIGNAL ;
    ANTENNAGATEAREA 0.126000 ;
    ANTENNADIFFAREA 0.869400 ;
    PORT
      LAYER met2 ;
        RECT 127.510 396.000 127.790 400.000 ;
    END
  END input_data[35]
  PIN input_data[36]
    DIRECTION INPUT ;
    USE SIGNAL ;
    ANTENNAGATEAREA 0.196500 ;
    ANTENNADIFFAREA 0.434700 ;
    PORT
      LAYER met2 ;
        RECT 130.730 396.000 131.010 400.000 ;
    END
  END input_data[36]
  PIN input_data[37]
    DIRECTION INPUT ;
    USE SIGNAL ;
    ANTENNAGATEAREA 0.213000 ;
    ANTENNADIFFAREA 1.304100 ;
    PORT
      LAYER met2 ;
        RECT 133.950 396.000 134.230 400.000 ;
    END
  END input_data[37]
  PIN input_data[38]
    DIRECTION INPUT ;
    USE SIGNAL ;
    ANTENNAGATEAREA 0.196500 ;
    ANTENNADIFFAREA 0.434700 ;
    PORT
      LAYER met2 ;
        RECT 137.170 396.000 137.450 400.000 ;
    END
  END input_data[38]
  PIN input_data[39]
    DIRECTION INPUT ;
    USE SIGNAL ;
    ANTENNAGATEAREA 0.196500 ;
    ANTENNADIFFAREA 0.434700 ;
    PORT
      LAYER met2 ;
        RECT 140.390 396.000 140.670 400.000 ;
    END
  END input_data[39]
  PIN input_data[3]
    DIRECTION INPUT ;
    USE SIGNAL ;
    ANTENNAGATEAREA 0.126000 ;
    ANTENNADIFFAREA 0.869400 ;
    PORT
      LAYER met2 ;
        RECT 24.470 396.000 24.750 400.000 ;
    END
  END input_data[3]
  PIN input_data[40]
    DIRECTION INPUT ;
    USE SIGNAL ;
    ANTENNAGATEAREA 0.196500 ;
    ANTENNADIFFAREA 0.434700 ;
    PORT
      LAYER met2 ;
        RECT 143.610 396.000 143.890 400.000 ;
    END
  END input_data[40]
  PIN input_data[41]
    DIRECTION INPUT ;
    USE SIGNAL ;
    ANTENNAGATEAREA 0.213000 ;
    ANTENNADIFFAREA 0.434700 ;
    PORT
      LAYER met2 ;
        RECT 146.830 396.000 147.110 400.000 ;
    END
  END input_data[41]
  PIN input_data[42]
    DIRECTION INPUT ;
    USE SIGNAL ;
    ANTENNAGATEAREA 0.213000 ;
    ANTENNADIFFAREA 0.869400 ;
    PORT
      LAYER met2 ;
        RECT 150.050 396.000 150.330 400.000 ;
    END
  END input_data[42]
  PIN input_data[43]
    DIRECTION INPUT ;
    USE SIGNAL ;
    ANTENNAGATEAREA 0.213000 ;
    ANTENNADIFFAREA 0.434700 ;
    PORT
      LAYER met2 ;
        RECT 153.270 396.000 153.550 400.000 ;
    END
  END input_data[43]
  PIN input_data[44]
    DIRECTION INPUT ;
    USE SIGNAL ;
    ANTENNAGATEAREA 0.213000 ;
    ANTENNADIFFAREA 0.434700 ;
    PORT
      LAYER met2 ;
        RECT 156.490 396.000 156.770 400.000 ;
    END
  END input_data[44]
  PIN input_data[45]
    DIRECTION INPUT ;
    USE SIGNAL ;
    ANTENNAGATEAREA 0.213000 ;
    ANTENNADIFFAREA 0.434700 ;
    PORT
      LAYER met2 ;
        RECT 159.710 396.000 159.990 400.000 ;
    END
  END input_data[45]
  PIN input_data[46]
    DIRECTION INPUT ;
    USE SIGNAL ;
    ANTENNAGATEAREA 0.213000 ;
    ANTENNADIFFAREA 1.304100 ;
    PORT
      LAYER met2 ;
        RECT 162.930 396.000 163.210 400.000 ;
    END
  END input_data[46]
  PIN input_data[47]
    DIRECTION INPUT ;
    USE SIGNAL ;
    ANTENNAGATEAREA 0.213000 ;
    ANTENNADIFFAREA 0.434700 ;
    PORT
      LAYER met2 ;
        RECT 166.150 396.000 166.430 400.000 ;
    END
  END input_data[47]
  PIN input_data[48]
    DIRECTION INPUT ;
    USE SIGNAL ;
    ANTENNAGATEAREA 0.196500 ;
    ANTENNADIFFAREA 0.869400 ;
    PORT
      LAYER met2 ;
        RECT 169.370 396.000 169.650 400.000 ;
    END
  END input_data[48]
  PIN input_data[49]
    DIRECTION INPUT ;
    USE SIGNAL ;
    ANTENNAGATEAREA 0.196500 ;
    ANTENNADIFFAREA 0.434700 ;
    PORT
      LAYER met2 ;
        RECT 172.590 396.000 172.870 400.000 ;
    END
  END input_data[49]
  PIN input_data[4]
    DIRECTION INPUT ;
    USE SIGNAL ;
    ANTENNAGATEAREA 0.196500 ;
    ANTENNADIFFAREA 0.434700 ;
    PORT
      LAYER met2 ;
        RECT 27.690 396.000 27.970 400.000 ;
    END
  END input_data[4]
  PIN input_data[50]
    DIRECTION INPUT ;
    USE SIGNAL ;
    ANTENNAGATEAREA 0.126000 ;
    ANTENNADIFFAREA 0.434700 ;
    PORT
      LAYER met2 ;
        RECT 175.810 396.000 176.090 400.000 ;
    END
  END input_data[50]
  PIN input_data[51]
    DIRECTION INPUT ;
    USE SIGNAL ;
    ANTENNAGATEAREA 0.196500 ;
    ANTENNADIFFAREA 0.434700 ;
    PORT
      LAYER met2 ;
        RECT 179.030 396.000 179.310 400.000 ;
    END
  END input_data[51]
  PIN input_data[52]
    DIRECTION INPUT ;
    USE SIGNAL ;
    ANTENNAGATEAREA 0.196500 ;
    ANTENNADIFFAREA 0.434700 ;
    PORT
      LAYER met2 ;
        RECT 182.250 396.000 182.530 400.000 ;
    END
  END input_data[52]
  PIN input_data[53]
    DIRECTION INPUT ;
    USE SIGNAL ;
    ANTENNAGATEAREA 0.196500 ;
    ANTENNADIFFAREA 0.869400 ;
    PORT
      LAYER met2 ;
        RECT 185.470 396.000 185.750 400.000 ;
    END
  END input_data[53]
  PIN input_data[54]
    DIRECTION INPUT ;
    USE SIGNAL ;
    ANTENNAGATEAREA 0.196500 ;
    ANTENNADIFFAREA 0.434700 ;
    PORT
      LAYER met2 ;
        RECT 188.690 396.000 188.970 400.000 ;
    END
  END input_data[54]
  PIN input_data[55]
    DIRECTION INPUT ;
    USE SIGNAL ;
    ANTENNAGATEAREA 0.126000 ;
    ANTENNADIFFAREA 0.434700 ;
    PORT
      LAYER met2 ;
        RECT 191.910 396.000 192.190 400.000 ;
    END
  END input_data[55]
  PIN input_data[56]
    DIRECTION INPUT ;
    USE SIGNAL ;
    ANTENNAGATEAREA 0.196500 ;
    ANTENNADIFFAREA 0.434700 ;
    PORT
      LAYER met2 ;
        RECT 195.130 396.000 195.410 400.000 ;
    END
  END input_data[56]
  PIN input_data[57]
    DIRECTION INPUT ;
    USE SIGNAL ;
    ANTENNAGATEAREA 0.196500 ;
    ANTENNADIFFAREA 0.869400 ;
    PORT
      LAYER met2 ;
        RECT 198.350 396.000 198.630 400.000 ;
    END
  END input_data[57]
  PIN input_data[58]
    DIRECTION INPUT ;
    USE SIGNAL ;
    ANTENNAGATEAREA 0.196500 ;
    ANTENNADIFFAREA 0.869400 ;
    PORT
      LAYER met2 ;
        RECT 201.570 396.000 201.850 400.000 ;
    END
  END input_data[58]
  PIN input_data[59]
    DIRECTION INPUT ;
    USE SIGNAL ;
    ANTENNAGATEAREA 0.213000 ;
    ANTENNADIFFAREA 0.434700 ;
    PORT
      LAYER met2 ;
        RECT 204.790 396.000 205.070 400.000 ;
    END
  END input_data[59]
  PIN input_data[5]
    DIRECTION INPUT ;
    USE SIGNAL ;
    ANTENNAGATEAREA 0.196500 ;
    ANTENNADIFFAREA 1.304100 ;
    PORT
      LAYER met2 ;
        RECT 30.910 396.000 31.190 400.000 ;
    END
  END input_data[5]
  PIN input_data[60]
    DIRECTION INPUT ;
    USE SIGNAL ;
    ANTENNAGATEAREA 0.213000 ;
    ANTENNADIFFAREA 0.434700 ;
    PORT
      LAYER met2 ;
        RECT 208.010 396.000 208.290 400.000 ;
    END
  END input_data[60]
  PIN input_data[61]
    DIRECTION INPUT ;
    USE SIGNAL ;
    ANTENNAGATEAREA 0.196500 ;
    ANTENNADIFFAREA 0.434700 ;
    PORT
      LAYER met2 ;
        RECT 211.230 396.000 211.510 400.000 ;
    END
  END input_data[61]
  PIN input_data[62]
    DIRECTION INPUT ;
    USE SIGNAL ;
    ANTENNAGATEAREA 0.213000 ;
    ANTENNADIFFAREA 0.434700 ;
    PORT
      LAYER met2 ;
        RECT 214.450 396.000 214.730 400.000 ;
    END
  END input_data[62]
  PIN input_data[63]
    DIRECTION INPUT ;
    USE SIGNAL ;
    PORT
      LAYER met2 ;
        RECT 217.670 396.000 217.950 400.000 ;
    END
  END input_data[63]
  PIN input_data[64]
    DIRECTION INPUT ;
    USE SIGNAL ;
    ANTENNAGATEAREA 0.213000 ;
    ANTENNADIFFAREA 0.434700 ;
    PORT
      LAYER met2 ;
        RECT 220.890 396.000 221.170 400.000 ;
    END
  END input_data[64]
  PIN input_data[65]
    DIRECTION INPUT ;
    USE SIGNAL ;
    ANTENNAGATEAREA 0.213000 ;
    ANTENNADIFFAREA 0.434700 ;
    PORT
      LAYER met2 ;
        RECT 224.110 396.000 224.390 400.000 ;
    END
  END input_data[65]
  PIN input_data[66]
    DIRECTION INPUT ;
    USE SIGNAL ;
    ANTENNAGATEAREA 0.196500 ;
    ANTENNADIFFAREA 0.434700 ;
    PORT
      LAYER met2 ;
        RECT 227.330 396.000 227.610 400.000 ;
    END
  END input_data[66]
  PIN input_data[67]
    DIRECTION INPUT ;
    USE SIGNAL ;
    ANTENNAGATEAREA 0.126000 ;
    ANTENNADIFFAREA 0.434700 ;
    PORT
      LAYER met2 ;
        RECT 230.550 396.000 230.830 400.000 ;
    END
  END input_data[67]
  PIN input_data[68]
    DIRECTION INPUT ;
    USE SIGNAL ;
    ANTENNAGATEAREA 0.213000 ;
    ANTENNADIFFAREA 0.434700 ;
    PORT
      LAYER met2 ;
        RECT 233.770 396.000 234.050 400.000 ;
    END
  END input_data[68]
  PIN input_data[69]
    DIRECTION INPUT ;
    USE SIGNAL ;
    ANTENNAGATEAREA 0.196500 ;
    ANTENNADIFFAREA 0.869400 ;
    PORT
      LAYER met2 ;
        RECT 236.990 396.000 237.270 400.000 ;
    END
  END input_data[69]
  PIN input_data[6]
    DIRECTION INPUT ;
    USE SIGNAL ;
    ANTENNAGATEAREA 0.196500 ;
    ANTENNADIFFAREA 0.869400 ;
    PORT
      LAYER met2 ;
        RECT 34.130 396.000 34.410 400.000 ;
    END
  END input_data[6]
  PIN input_data[70]
    DIRECTION INPUT ;
    USE SIGNAL ;
    ANTENNAGATEAREA 0.196500 ;
    ANTENNADIFFAREA 0.869400 ;
    PORT
      LAYER met2 ;
        RECT 240.210 396.000 240.490 400.000 ;
    END
  END input_data[70]
  PIN input_data[71]
    DIRECTION INPUT ;
    USE SIGNAL ;
    ANTENNAGATEAREA 0.196500 ;
    ANTENNADIFFAREA 0.869400 ;
    PORT
      LAYER met2 ;
        RECT 243.430 396.000 243.710 400.000 ;
    END
  END input_data[71]
  PIN input_data[72]
    DIRECTION INPUT ;
    USE SIGNAL ;
    ANTENNAGATEAREA 0.196500 ;
    ANTENNADIFFAREA 0.434700 ;
    PORT
      LAYER met2 ;
        RECT 246.650 396.000 246.930 400.000 ;
    END
  END input_data[72]
  PIN input_data[73]
    DIRECTION INPUT ;
    USE SIGNAL ;
    ANTENNAGATEAREA 0.159000 ;
    ANTENNADIFFAREA 0.434700 ;
    PORT
      LAYER met2 ;
        RECT 249.870 396.000 250.150 400.000 ;
    END
  END input_data[73]
  PIN input_data[74]
    DIRECTION INPUT ;
    USE SIGNAL ;
    ANTENNAGATEAREA 0.213000 ;
    ANTENNADIFFAREA 0.434700 ;
    PORT
      LAYER met2 ;
        RECT 253.090 396.000 253.370 400.000 ;
    END
  END input_data[74]
  PIN input_data[75]
    DIRECTION INPUT ;
    USE SIGNAL ;
    ANTENNAGATEAREA 0.196500 ;
    ANTENNADIFFAREA 0.869400 ;
    PORT
      LAYER met2 ;
        RECT 256.310 396.000 256.590 400.000 ;
    END
  END input_data[75]
  PIN input_data[76]
    DIRECTION INPUT ;
    USE SIGNAL ;
    ANTENNAGATEAREA 0.196500 ;
    ANTENNADIFFAREA 0.434700 ;
    PORT
      LAYER met2 ;
        RECT 259.530 396.000 259.810 400.000 ;
    END
  END input_data[76]
  PIN input_data[77]
    DIRECTION INPUT ;
    USE SIGNAL ;
    ANTENNAGATEAREA 0.213000 ;
    ANTENNADIFFAREA 0.434700 ;
    PORT
      LAYER met2 ;
        RECT 262.750 396.000 263.030 400.000 ;
    END
  END input_data[77]
  PIN input_data[78]
    DIRECTION INPUT ;
    USE SIGNAL ;
    ANTENNAGATEAREA 0.126000 ;
    ANTENNADIFFAREA 0.434700 ;
    PORT
      LAYER met2 ;
        RECT 265.970 396.000 266.250 400.000 ;
    END
  END input_data[78]
  PIN input_data[79]
    DIRECTION INPUT ;
    USE SIGNAL ;
    PORT
      LAYER met2 ;
        RECT 269.190 396.000 269.470 400.000 ;
    END
  END input_data[79]
  PIN input_data[7]
    DIRECTION INPUT ;
    USE SIGNAL ;
    ANTENNAGATEAREA 0.196500 ;
    ANTENNADIFFAREA 1.304100 ;
    PORT
      LAYER met2 ;
        RECT 37.350 396.000 37.630 400.000 ;
    END
  END input_data[7]
  PIN input_data[80]
    DIRECTION INPUT ;
    USE SIGNAL ;
    ANTENNAGATEAREA 0.196500 ;
    ANTENNADIFFAREA 0.434700 ;
    PORT
      LAYER met2 ;
        RECT 272.410 396.000 272.690 400.000 ;
    END
  END input_data[80]
  PIN input_data[81]
    DIRECTION INPUT ;
    USE SIGNAL ;
    ANTENNAGATEAREA 0.126000 ;
    ANTENNADIFFAREA 0.434700 ;
    PORT
      LAYER met2 ;
        RECT 275.630 396.000 275.910 400.000 ;
    END
  END input_data[81]
  PIN input_data[82]
    DIRECTION INPUT ;
    USE SIGNAL ;
    ANTENNAGATEAREA 0.213000 ;
    ANTENNADIFFAREA 0.434700 ;
    PORT
      LAYER met2 ;
        RECT 278.850 396.000 279.130 400.000 ;
    END
  END input_data[82]
  PIN input_data[83]
    DIRECTION INPUT ;
    USE SIGNAL ;
    ANTENNAGATEAREA 0.213000 ;
    ANTENNADIFFAREA 0.434700 ;
    PORT
      LAYER met2 ;
        RECT 282.070 396.000 282.350 400.000 ;
    END
  END input_data[83]
  PIN input_data[84]
    DIRECTION INPUT ;
    USE SIGNAL ;
    ANTENNAGATEAREA 0.213000 ;
    ANTENNADIFFAREA 0.434700 ;
    PORT
      LAYER met2 ;
        RECT 285.290 396.000 285.570 400.000 ;
    END
  END input_data[84]
  PIN input_data[85]
    DIRECTION INPUT ;
    USE SIGNAL ;
    ANTENNAGATEAREA 0.213000 ;
    ANTENNADIFFAREA 0.434700 ;
    PORT
      LAYER met2 ;
        RECT 288.510 396.000 288.790 400.000 ;
    END
  END input_data[85]
  PIN input_data[86]
    DIRECTION INPUT ;
    USE SIGNAL ;
    ANTENNAGATEAREA 0.213000 ;
    ANTENNADIFFAREA 0.434700 ;
    PORT
      LAYER met2 ;
        RECT 291.730 396.000 292.010 400.000 ;
    END
  END input_data[86]
  PIN input_data[87]
    DIRECTION INPUT ;
    USE SIGNAL ;
    ANTENNAGATEAREA 0.159000 ;
    ANTENNADIFFAREA 0.434700 ;
    PORT
      LAYER met2 ;
        RECT 294.950 396.000 295.230 400.000 ;
    END
  END input_data[87]
  PIN input_data[88]
    DIRECTION INPUT ;
    USE SIGNAL ;
    ANTENNAGATEAREA 0.247500 ;
    ANTENNADIFFAREA 0.434700 ;
    PORT
      LAYER met2 ;
        RECT 298.170 396.000 298.450 400.000 ;
    END
  END input_data[88]
  PIN input_data[89]
    DIRECTION INPUT ;
    USE SIGNAL ;
    ANTENNAGATEAREA 0.213000 ;
    ANTENNADIFFAREA 0.434700 ;
    PORT
      LAYER met2 ;
        RECT 301.390 396.000 301.670 400.000 ;
    END
  END input_data[89]
  PIN input_data[8]
    DIRECTION INPUT ;
    USE SIGNAL ;
    ANTENNAGATEAREA 0.196500 ;
    ANTENNADIFFAREA 0.434700 ;
    PORT
      LAYER met2 ;
        RECT 40.570 396.000 40.850 400.000 ;
    END
  END input_data[8]
  PIN input_data[90]
    DIRECTION INPUT ;
    USE SIGNAL ;
    ANTENNAGATEAREA 0.213000 ;
    ANTENNADIFFAREA 0.434700 ;
    PORT
      LAYER met2 ;
        RECT 304.610 396.000 304.890 400.000 ;
    END
  END input_data[90]
  PIN input_data[91]
    DIRECTION INPUT ;
    USE SIGNAL ;
    ANTENNAGATEAREA 0.213000 ;
    ANTENNADIFFAREA 0.434700 ;
    PORT
      LAYER met2 ;
        RECT 307.830 396.000 308.110 400.000 ;
    END
  END input_data[91]
  PIN input_data[92]
    DIRECTION INPUT ;
    USE SIGNAL ;
    ANTENNAGATEAREA 0.213000 ;
    ANTENNADIFFAREA 0.434700 ;
    PORT
      LAYER met2 ;
        RECT 311.050 396.000 311.330 400.000 ;
    END
  END input_data[92]
  PIN input_data[93]
    DIRECTION INPUT ;
    USE SIGNAL ;
    ANTENNAGATEAREA 0.247500 ;
    ANTENNADIFFAREA 0.434700 ;
    PORT
      LAYER met2 ;
        RECT 314.270 396.000 314.550 400.000 ;
    END
  END input_data[93]
  PIN input_data[94]
    DIRECTION INPUT ;
    USE SIGNAL ;
    ANTENNAGATEAREA 0.213000 ;
    ANTENNADIFFAREA 0.434700 ;
    PORT
      LAYER met2 ;
        RECT 317.490 396.000 317.770 400.000 ;
    END
  END input_data[94]
  PIN input_data[95]
    DIRECTION INPUT ;
    USE SIGNAL ;
    ANTENNAGATEAREA 0.213000 ;
    ANTENNADIFFAREA 0.434700 ;
    PORT
      LAYER met2 ;
        RECT 320.710 396.000 320.990 400.000 ;
    END
  END input_data[95]
  PIN input_data[96]
    DIRECTION INPUT ;
    USE SIGNAL ;
    ANTENNAGATEAREA 0.196500 ;
    ANTENNADIFFAREA 0.434700 ;
    PORT
      LAYER met2 ;
        RECT 323.930 396.000 324.210 400.000 ;
    END
  END input_data[96]
  PIN input_data[97]
    DIRECTION INPUT ;
    USE SIGNAL ;
    ANTENNAGATEAREA 0.196500 ;
    ANTENNADIFFAREA 0.434700 ;
    PORT
      LAYER met2 ;
        RECT 327.150 396.000 327.430 400.000 ;
    END
  END input_data[97]
  PIN input_data[98]
    DIRECTION INPUT ;
    USE SIGNAL ;
    ANTENNAGATEAREA 0.196500 ;
    ANTENNADIFFAREA 0.434700 ;
    PORT
      LAYER met2 ;
        RECT 330.370 396.000 330.650 400.000 ;
    END
  END input_data[98]
  PIN input_data[99]
    DIRECTION INPUT ;
    USE SIGNAL ;
    ANTENNAGATEAREA 0.196500 ;
    ANTENNADIFFAREA 0.434700 ;
    PORT
      LAYER met2 ;
        RECT 333.590 396.000 333.870 400.000 ;
    END
  END input_data[99]
  PIN input_data[9]
    DIRECTION INPUT ;
    USE SIGNAL ;
    ANTENNAGATEAREA 0.213000 ;
    ANTENNADIFFAREA 0.869400 ;
    PORT
      LAYER met2 ;
        RECT 43.790 396.000 44.070 400.000 ;
    END
  END input_data[9]
  PIN output_high[0]
    DIRECTION OUTPUT ;
    USE SIGNAL ;
    ANTENNADIFFAREA 0.891000 ;
    PORT
      LAYER met3 ;
        RECT 0.000 15.000 4.000 15.600 ;
    END
  END output_high[0]
  PIN output_high[10]
    DIRECTION OUTPUT ;
    USE SIGNAL ;
    ANTENNADIFFAREA 0.795200 ;
    PORT
      LAYER met3 ;
        RECT 0.000 259.800 4.000 260.400 ;
    END
  END output_high[10]
  PIN output_high[11]
    DIRECTION OUTPUT ;
    USE SIGNAL ;
    ANTENNADIFFAREA 0.795200 ;
    PORT
      LAYER met3 ;
        RECT 0.000 284.280 4.000 284.880 ;
    END
  END output_high[11]
  PIN output_high[12]
    DIRECTION OUTPUT ;
    USE SIGNAL ;
    ANTENNADIFFAREA 0.795200 ;
    PORT
      LAYER met3 ;
        RECT 0.000 308.760 4.000 309.360 ;
    END
  END output_high[12]
  PIN output_high[13]
    DIRECTION OUTPUT ;
    USE SIGNAL ;
    ANTENNADIFFAREA 0.795200 ;
    PORT
      LAYER met3 ;
        RECT 0.000 333.240 4.000 333.840 ;
    END
  END output_high[13]
  PIN output_high[14]
    DIRECTION OUTPUT ;
    USE SIGNAL ;
    ANTENNADIFFAREA 0.795200 ;
    PORT
      LAYER met3 ;
        RECT 0.000 357.720 4.000 358.320 ;
    END
  END output_high[14]
  PIN output_high[15]
    DIRECTION OUTPUT ;
    USE SIGNAL ;
    ANTENNADIFFAREA 0.891000 ;
    PORT
      LAYER met3 ;
        RECT 0.000 382.200 4.000 382.800 ;
    END
  END output_high[15]
  PIN output_high[1]
    DIRECTION OUTPUT ;
    USE SIGNAL ;
    ANTENNADIFFAREA 0.795200 ;
    PORT
      LAYER met3 ;
        RECT 0.000 39.480 4.000 40.080 ;
    END
  END output_high[1]
  PIN output_high[2]
    DIRECTION OUTPUT ;
    USE SIGNAL ;
    ANTENNADIFFAREA 0.795200 ;
    PORT
      LAYER met3 ;
        RECT 0.000 63.960 4.000 64.560 ;
    END
  END output_high[2]
  PIN output_high[3]
    DIRECTION OUTPUT ;
    USE SIGNAL ;
    ANTENNADIFFAREA 0.795200 ;
    PORT
      LAYER met3 ;
        RECT 0.000 88.440 4.000 89.040 ;
    END
  END output_high[3]
  PIN output_high[4]
    DIRECTION OUTPUT ;
    USE SIGNAL ;
    ANTENNADIFFAREA 0.795200 ;
    PORT
      LAYER met3 ;
        RECT 0.000 112.920 4.000 113.520 ;
    END
  END output_high[4]
  PIN output_high[5]
    DIRECTION OUTPUT ;
    USE SIGNAL ;
    ANTENNADIFFAREA 0.795200 ;
    PORT
      LAYER met3 ;
        RECT 0.000 137.400 4.000 138.000 ;
    END
  END output_high[5]
  PIN output_high[6]
    DIRECTION OUTPUT ;
    USE SIGNAL ;
    ANTENNADIFFAREA 0.795200 ;
    PORT
      LAYER met3 ;
        RECT 0.000 161.880 4.000 162.480 ;
    END
  END output_high[6]
  PIN output_high[7]
    DIRECTION OUTPUT ;
    USE SIGNAL ;
    ANTENNADIFFAREA 0.795200 ;
    PORT
      LAYER met3 ;
        RECT 0.000 186.360 4.000 186.960 ;
    END
  END output_high[7]
  PIN output_high[8]
    DIRECTION OUTPUT ;
    USE SIGNAL ;
    ANTENNADIFFAREA 0.795200 ;
    PORT
      LAYER met3 ;
        RECT 0.000 210.840 4.000 211.440 ;
    END
  END output_high[8]
  PIN output_high[9]
    DIRECTION OUTPUT ;
    USE SIGNAL ;
    ANTENNADIFFAREA 0.795200 ;
    PORT
      LAYER met3 ;
        RECT 0.000 235.320 4.000 235.920 ;
    END
  END output_high[9]
  PIN tap[0]
    DIRECTION INPUT ;
    USE SIGNAL ;
    ANTENNAGATEAREA 0.213000 ;
    ANTENNADIFFAREA 0.434700 ;
    PORT
      LAYER met2 ;
        RECT 100.370 0.000 100.650 4.000 ;
    END
  END tap[0]
  PIN tap[1]
    DIRECTION INPUT ;
    USE SIGNAL ;
    ANTENNAGATEAREA 0.213000 ;
    ANTENNADIFFAREA 0.434700 ;
    PORT
      LAYER met2 ;
        RECT 300.010 0.000 300.290 4.000 ;
    END
  END tap[1]
  PIN tap[2]
    DIRECTION INPUT ;
    USE SIGNAL ;
    ANTENNAGATEAREA 0.247500 ;
    ANTENNADIFFAREA 0.434700 ;
    PORT
      LAYER met2 ;
        RECT 499.650 0.000 499.930 4.000 ;
    END
  END tap[2]
  PIN tap[3]
    DIRECTION INPUT ;
    USE SIGNAL ;
    ANTENNAGATEAREA 0.426000 ;
    ANTENNADIFFAREA 0.434700 ;
    PORT
      LAYER met2 ;
        RECT 699.290 0.000 699.570 4.000 ;
    END
  END tap[3]
  OBS
      LAYER li1 ;
        RECT 100.280 100.555 699.660 299.285 ;
      LAYER met1 ;
        RECT 17.090 17.380 778.250 396.060 ;
      LAYER met2 ;
        RECT 15.370 395.720 17.750 396.170 ;
        RECT 18.590 395.720 20.970 396.170 ;
        RECT 21.810 395.720 24.190 396.170 ;
        RECT 25.030 395.720 27.410 396.170 ;
        RECT 28.250 395.720 30.630 396.170 ;
        RECT 31.470 395.720 33.850 396.170 ;
        RECT 34.690 395.720 37.070 396.170 ;
        RECT 37.910 395.720 40.290 396.170 ;
        RECT 41.130 395.720 43.510 396.170 ;
        RECT 44.350 395.720 46.730 396.170 ;
        RECT 47.570 395.720 49.950 396.170 ;
        RECT 50.790 395.720 53.170 396.170 ;
        RECT 54.010 395.720 56.390 396.170 ;
        RECT 57.230 395.720 59.610 396.170 ;
        RECT 60.450 395.720 62.830 396.170 ;
        RECT 63.670 395.720 66.050 396.170 ;
        RECT 66.890 395.720 69.270 396.170 ;
        RECT 70.110 395.720 72.490 396.170 ;
        RECT 73.330 395.720 75.710 396.170 ;
        RECT 76.550 395.720 78.930 396.170 ;
        RECT 79.770 395.720 82.150 396.170 ;
        RECT 82.990 395.720 85.370 396.170 ;
        RECT 86.210 395.720 88.590 396.170 ;
        RECT 89.430 395.720 91.810 396.170 ;
        RECT 92.650 395.720 95.030 396.170 ;
        RECT 95.870 395.720 98.250 396.170 ;
        RECT 99.090 395.720 101.470 396.170 ;
        RECT 102.310 395.720 104.690 396.170 ;
        RECT 105.530 395.720 107.910 396.170 ;
        RECT 108.750 395.720 111.130 396.170 ;
        RECT 111.970 395.720 114.350 396.170 ;
        RECT 115.190 395.720 117.570 396.170 ;
        RECT 118.410 395.720 120.790 396.170 ;
        RECT 121.630 395.720 124.010 396.170 ;
        RECT 124.850 395.720 127.230 396.170 ;
        RECT 128.070 395.720 130.450 396.170 ;
        RECT 131.290 395.720 133.670 396.170 ;
        RECT 134.510 395.720 136.890 396.170 ;
        RECT 137.730 395.720 140.110 396.170 ;
        RECT 140.950 395.720 143.330 396.170 ;
        RECT 144.170 395.720 146.550 396.170 ;
        RECT 147.390 395.720 149.770 396.170 ;
        RECT 150.610 395.720 152.990 396.170 ;
        RECT 153.830 395.720 156.210 396.170 ;
        RECT 157.050 395.720 159.430 396.170 ;
        RECT 160.270 395.720 162.650 396.170 ;
        RECT 163.490 395.720 165.870 396.170 ;
        RECT 166.710 395.720 169.090 396.170 ;
        RECT 169.930 395.720 172.310 396.170 ;
        RECT 173.150 395.720 175.530 396.170 ;
        RECT 176.370 395.720 178.750 396.170 ;
        RECT 179.590 395.720 181.970 396.170 ;
        RECT 182.810 395.720 185.190 396.170 ;
        RECT 186.030 395.720 188.410 396.170 ;
        RECT 189.250 395.720 191.630 396.170 ;
        RECT 192.470 395.720 194.850 396.170 ;
        RECT 195.690 395.720 198.070 396.170 ;
        RECT 198.910 395.720 201.290 396.170 ;
        RECT 202.130 395.720 204.510 396.170 ;
        RECT 205.350 395.720 207.730 396.170 ;
        RECT 208.570 395.720 210.950 396.170 ;
        RECT 211.790 395.720 214.170 396.170 ;
        RECT 215.010 395.720 217.390 396.170 ;
        RECT 218.230 395.720 220.610 396.170 ;
        RECT 221.450 395.720 223.830 396.170 ;
        RECT 224.670 395.720 227.050 396.170 ;
        RECT 227.890 395.720 230.270 396.170 ;
        RECT 231.110 395.720 233.490 396.170 ;
        RECT 234.330 395.720 236.710 396.170 ;
        RECT 237.550 395.720 239.930 396.170 ;
        RECT 240.770 395.720 243.150 396.170 ;
        RECT 243.990 395.720 246.370 396.170 ;
        RECT 247.210 395.720 249.590 396.170 ;
        RECT 250.430 395.720 252.810 396.170 ;
        RECT 253.650 395.720 256.030 396.170 ;
        RECT 256.870 395.720 259.250 396.170 ;
        RECT 260.090 395.720 262.470 396.170 ;
        RECT 263.310 395.720 265.690 396.170 ;
        RECT 266.530 395.720 268.910 396.170 ;
        RECT 269.750 395.720 272.130 396.170 ;
        RECT 272.970 395.720 275.350 396.170 ;
        RECT 276.190 395.720 278.570 396.170 ;
        RECT 279.410 395.720 281.790 396.170 ;
        RECT 282.630 395.720 285.010 396.170 ;
        RECT 285.850 395.720 288.230 396.170 ;
        RECT 289.070 395.720 291.450 396.170 ;
        RECT 292.290 395.720 294.670 396.170 ;
        RECT 295.510 395.720 297.890 396.170 ;
        RECT 298.730 395.720 301.110 396.170 ;
        RECT 301.950 395.720 304.330 396.170 ;
        RECT 305.170 395.720 307.550 396.170 ;
        RECT 308.390 395.720 310.770 396.170 ;
        RECT 311.610 395.720 313.990 396.170 ;
        RECT 314.830 395.720 317.210 396.170 ;
        RECT 318.050 395.720 320.430 396.170 ;
        RECT 321.270 395.720 323.650 396.170 ;
        RECT 324.490 395.720 326.870 396.170 ;
        RECT 327.710 395.720 330.090 396.170 ;
        RECT 330.930 395.720 333.310 396.170 ;
        RECT 334.150 395.720 336.530 396.170 ;
        RECT 337.370 395.720 339.750 396.170 ;
        RECT 340.590 395.720 342.970 396.170 ;
        RECT 343.810 395.720 346.190 396.170 ;
        RECT 347.030 395.720 349.410 396.170 ;
        RECT 350.250 395.720 352.630 396.170 ;
        RECT 353.470 395.720 355.850 396.170 ;
        RECT 356.690 395.720 359.070 396.170 ;
        RECT 359.910 395.720 362.290 396.170 ;
        RECT 363.130 395.720 365.510 396.170 ;
        RECT 366.350 395.720 368.730 396.170 ;
        RECT 369.570 395.720 371.950 396.170 ;
        RECT 372.790 395.720 375.170 396.170 ;
        RECT 376.010 395.720 378.390 396.170 ;
        RECT 379.230 395.720 381.610 396.170 ;
        RECT 382.450 395.720 384.830 396.170 ;
        RECT 385.670 395.720 388.050 396.170 ;
        RECT 388.890 395.720 391.270 396.170 ;
        RECT 392.110 395.720 394.490 396.170 ;
        RECT 395.330 395.720 397.710 396.170 ;
        RECT 398.550 395.720 400.930 396.170 ;
        RECT 401.770 395.720 404.150 396.170 ;
        RECT 404.990 395.720 407.370 396.170 ;
        RECT 408.210 395.720 410.590 396.170 ;
        RECT 411.430 395.720 413.810 396.170 ;
        RECT 414.650 395.720 417.030 396.170 ;
        RECT 417.870 395.720 420.250 396.170 ;
        RECT 421.090 395.720 423.470 396.170 ;
        RECT 424.310 395.720 426.690 396.170 ;
        RECT 427.530 395.720 429.910 396.170 ;
        RECT 430.750 395.720 433.130 396.170 ;
        RECT 433.970 395.720 436.350 396.170 ;
        RECT 437.190 395.720 439.570 396.170 ;
        RECT 440.410 395.720 442.790 396.170 ;
        RECT 443.630 395.720 446.010 396.170 ;
        RECT 446.850 395.720 449.230 396.170 ;
        RECT 450.070 395.720 452.450 396.170 ;
        RECT 453.290 395.720 455.670 396.170 ;
        RECT 456.510 395.720 458.890 396.170 ;
        RECT 459.730 395.720 462.110 396.170 ;
        RECT 462.950 395.720 465.330 396.170 ;
        RECT 466.170 395.720 468.550 396.170 ;
        RECT 469.390 395.720 471.770 396.170 ;
        RECT 472.610 395.720 474.990 396.170 ;
        RECT 475.830 395.720 478.210 396.170 ;
        RECT 479.050 395.720 481.430 396.170 ;
        RECT 482.270 395.720 484.650 396.170 ;
        RECT 485.490 395.720 487.870 396.170 ;
        RECT 488.710 395.720 491.090 396.170 ;
        RECT 491.930 395.720 494.310 396.170 ;
        RECT 495.150 395.720 497.530 396.170 ;
        RECT 498.370 395.720 500.750 396.170 ;
        RECT 501.590 395.720 503.970 396.170 ;
        RECT 504.810 395.720 507.190 396.170 ;
        RECT 508.030 395.720 510.410 396.170 ;
        RECT 511.250 395.720 513.630 396.170 ;
        RECT 514.470 395.720 516.850 396.170 ;
        RECT 517.690 395.720 520.070 396.170 ;
        RECT 520.910 395.720 523.290 396.170 ;
        RECT 524.130 395.720 526.510 396.170 ;
        RECT 527.350 395.720 529.730 396.170 ;
        RECT 530.570 395.720 532.950 396.170 ;
        RECT 533.790 395.720 536.170 396.170 ;
        RECT 537.010 395.720 539.390 396.170 ;
        RECT 540.230 395.720 542.610 396.170 ;
        RECT 543.450 395.720 545.830 396.170 ;
        RECT 546.670 395.720 549.050 396.170 ;
        RECT 549.890 395.720 552.270 396.170 ;
        RECT 553.110 395.720 555.490 396.170 ;
        RECT 556.330 395.720 558.710 396.170 ;
        RECT 559.550 395.720 561.930 396.170 ;
        RECT 562.770 395.720 565.150 396.170 ;
        RECT 565.990 395.720 568.370 396.170 ;
        RECT 569.210 395.720 571.590 396.170 ;
        RECT 572.430 395.720 574.810 396.170 ;
        RECT 575.650 395.720 578.030 396.170 ;
        RECT 578.870 395.720 581.250 396.170 ;
        RECT 582.090 395.720 584.470 396.170 ;
        RECT 585.310 395.720 587.690 396.170 ;
        RECT 588.530 395.720 590.910 396.170 ;
        RECT 591.750 395.720 594.130 396.170 ;
        RECT 594.970 395.720 597.350 396.170 ;
        RECT 598.190 395.720 600.570 396.170 ;
        RECT 601.410 395.720 603.790 396.170 ;
        RECT 604.630 395.720 607.010 396.170 ;
        RECT 607.850 395.720 610.230 396.170 ;
        RECT 611.070 395.720 613.450 396.170 ;
        RECT 614.290 395.720 616.670 396.170 ;
        RECT 617.510 395.720 619.890 396.170 ;
        RECT 620.730 395.720 623.110 396.170 ;
        RECT 623.950 395.720 626.330 396.170 ;
        RECT 627.170 395.720 629.550 396.170 ;
        RECT 630.390 395.720 632.770 396.170 ;
        RECT 633.610 395.720 635.990 396.170 ;
        RECT 636.830 395.720 639.210 396.170 ;
        RECT 640.050 395.720 642.430 396.170 ;
        RECT 643.270 395.720 645.650 396.170 ;
        RECT 646.490 395.720 648.870 396.170 ;
        RECT 649.710 395.720 652.090 396.170 ;
        RECT 652.930 395.720 655.310 396.170 ;
        RECT 656.150 395.720 658.530 396.170 ;
        RECT 659.370 395.720 661.750 396.170 ;
        RECT 662.590 395.720 664.970 396.170 ;
        RECT 665.810 395.720 668.190 396.170 ;
        RECT 669.030 395.720 671.410 396.170 ;
        RECT 672.250 395.720 674.630 396.170 ;
        RECT 675.470 395.720 677.850 396.170 ;
        RECT 678.690 395.720 681.070 396.170 ;
        RECT 681.910 395.720 684.290 396.170 ;
        RECT 685.130 395.720 687.510 396.170 ;
        RECT 688.350 395.720 690.730 396.170 ;
        RECT 691.570 395.720 693.950 396.170 ;
        RECT 694.790 395.720 697.170 396.170 ;
        RECT 698.010 395.720 700.390 396.170 ;
        RECT 701.230 395.720 703.610 396.170 ;
        RECT 704.450 395.720 706.830 396.170 ;
        RECT 707.670 395.720 710.050 396.170 ;
        RECT 710.890 395.720 713.270 396.170 ;
        RECT 714.110 395.720 716.490 396.170 ;
        RECT 717.330 395.720 719.710 396.170 ;
        RECT 720.550 395.720 722.930 396.170 ;
        RECT 723.770 395.720 726.150 396.170 ;
        RECT 726.990 395.720 729.370 396.170 ;
        RECT 730.210 395.720 732.590 396.170 ;
        RECT 733.430 395.720 735.810 396.170 ;
        RECT 736.650 395.720 739.030 396.170 ;
        RECT 739.870 395.720 742.250 396.170 ;
        RECT 743.090 395.720 745.470 396.170 ;
        RECT 746.310 395.720 748.690 396.170 ;
        RECT 749.530 395.720 751.910 396.170 ;
        RECT 752.750 395.720 755.130 396.170 ;
        RECT 755.970 395.720 758.350 396.170 ;
        RECT 759.190 395.720 761.570 396.170 ;
        RECT 762.410 395.720 764.790 396.170 ;
        RECT 765.630 395.720 768.010 396.170 ;
        RECT 768.850 395.720 771.230 396.170 ;
        RECT 772.070 395.720 774.450 396.170 ;
        RECT 775.290 395.720 777.670 396.170 ;
        RECT 14.810 4.280 778.220 395.720 ;
        RECT 14.810 4.000 100.090 4.280 ;
        RECT 100.930 4.000 299.730 4.280 ;
        RECT 300.570 4.000 499.370 4.280 ;
        RECT 500.210 4.000 699.010 4.280 ;
        RECT 699.850 4.000 778.220 4.280 ;
      LAYER met3 ;
        RECT 4.400 381.800 796.000 382.665 ;
        RECT 4.000 358.720 796.000 381.800 ;
        RECT 4.400 357.320 796.000 358.720 ;
        RECT 4.000 334.240 796.000 357.320 ;
        RECT 4.400 332.840 796.000 334.240 ;
        RECT 4.000 309.760 796.000 332.840 ;
        RECT 4.400 308.360 796.000 309.760 ;
        RECT 4.000 285.280 796.000 308.360 ;
        RECT 4.400 283.880 796.000 285.280 ;
        RECT 4.000 260.800 796.000 283.880 ;
        RECT 4.400 259.400 796.000 260.800 ;
        RECT 4.000 236.320 796.000 259.400 ;
        RECT 4.400 234.920 796.000 236.320 ;
        RECT 4.000 211.840 796.000 234.920 ;
        RECT 4.400 210.440 796.000 211.840 ;
        RECT 4.000 199.600 796.000 210.440 ;
        RECT 4.000 198.200 795.600 199.600 ;
        RECT 4.000 187.360 796.000 198.200 ;
        RECT 4.400 185.960 796.000 187.360 ;
        RECT 4.000 162.880 796.000 185.960 ;
        RECT 4.400 161.480 796.000 162.880 ;
        RECT 4.000 138.400 796.000 161.480 ;
        RECT 4.400 137.000 796.000 138.400 ;
        RECT 4.000 113.920 796.000 137.000 ;
        RECT 4.400 112.520 796.000 113.920 ;
        RECT 4.000 89.440 796.000 112.520 ;
        RECT 4.400 88.040 796.000 89.440 ;
        RECT 4.000 64.960 796.000 88.040 ;
        RECT 4.400 63.560 796.000 64.960 ;
        RECT 4.000 40.480 796.000 63.560 ;
        RECT 4.400 39.080 796.000 40.480 ;
        RECT 4.000 16.000 796.000 39.080 ;
        RECT 4.400 15.135 796.000 16.000 ;
      LAYER met4 ;
        RECT 72.055 299.840 696.145 379.265 ;
        RECT 72.055 100.000 115.400 299.840 ;
        RECT 117.800 100.000 118.700 299.840 ;
        RECT 121.100 100.000 269.000 299.840 ;
        RECT 271.400 100.000 272.300 299.840 ;
        RECT 274.700 100.000 422.600 299.840 ;
        RECT 425.000 100.000 425.900 299.840 ;
        RECT 428.300 100.000 576.200 299.840 ;
        RECT 578.600 100.000 579.500 299.840 ;
        RECT 581.900 100.000 696.145 299.840 ;
        RECT 72.055 92.655 696.145 100.000 ;
  END
END highpass
END LIBRARY

